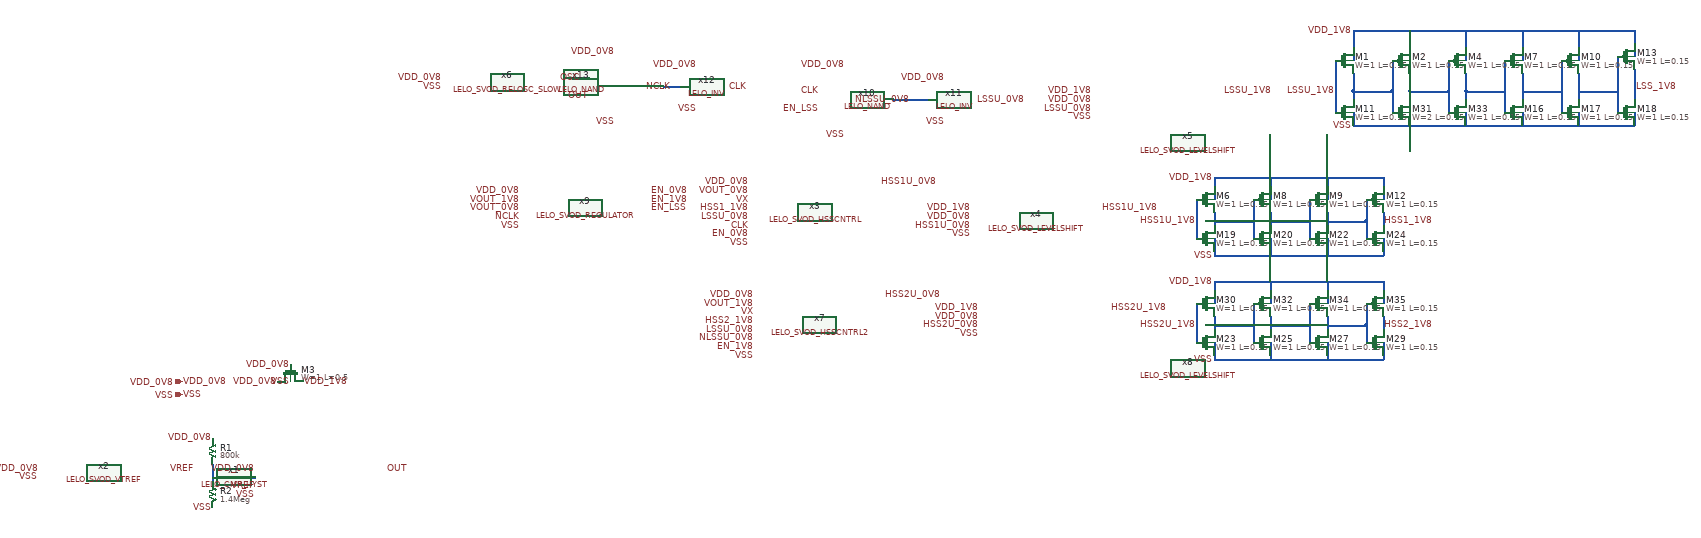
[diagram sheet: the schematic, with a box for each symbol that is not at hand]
v {xschem version=3.4.8RC file_version=1.2}
G {}
K {}
V {}
S {}
E {}
N -240 -50 -240 -10 {lab=#net1}
N -240 -20 -140 -20 {lab=#net1}
N 2390 -860 2390 -830 {lab=VSS}
N 2780 -950 2780 -890 {lab=#net2}
N 2780 -860 2780 -830 {lab=VSS}
N 2740 -980 2740 -860 {lab=#net3}
N 2390 -910 2480 -910 {lab=#net4}
N 2910 -950 2910 -890 {lab=#net5}
N 2910 -860 2910 -830 {lab=VSS}
N 2870 -980 2870 -860 {lab=#net2}
N 2780 -910 2870 -910 {lab=#net2}
N 3040 -960 3040 -890 {lab=LSS_1V8}
N 3040 -860 3040 -830 {lab=VSS}
N 3000 -990 3000 -860 {lab=#net5}
N 2910 -910 3000 -910 {lab=#net5}
N 2390 -1050 2970 -1050 {lab=VDD_1V8}
N 2780 -1050 2780 -1010 {lab=VDD_1V8}
N 2910 -1050 2910 -1010 {lab=VDD_1V8}
N 3040 -1050 3040 -1020 {lab=VDD_1V8}
N 2390 -1050 2390 -1010 {lab=VDD_1V8}
N 2390 -950 2390 -910 {lab=#net4}
N 2390 -910 2390 -890 {lab=#net4}
N 2350 -980 2350 -910 {lab=LSSU_1V8}
N 2350 -910 2350 -860 {lab=LSSU_1V8}
N 2070 -710 2070 -690 {lab=VDD_1V8}
N 2200 -710 2200 -690 {lab=VDD_1V8}
N 2070 -570 2070 -540 {lab=VSS}
N 2200 -570 2200 -540 {lab=VSS}
N 2030 -660 2030 -610 {lab=HSS1U_1V8}
N 2030 -610 2030 -570 {lab=HSS1U_1V8}
N 2070 -630 2070 -600 {lab=#net6}
N 2070 -540 2070 -530 {lab=VSS}
N 2070 -610 2160 -610 {lab=#net6}
N 2160 -660 2160 -610 {lab=#net6}
N 2160 -610 2160 -570 {lab=#net6}
N 2200 -630 2200 -600 {lab=#net7}
N 2200 -540 2200 -530 {lab=VSS}
N 2330 -710 2330 -690 {lab=VDD_1V8}
N 2330 -570 2330 -540 {lab=VSS}
N 2200 -610 2290 -610 {lab=#net7}
N 2290 -660 2290 -610 {lab=#net7}
N 2290 -610 2290 -570 {lab=#net7}
N 2330 -630 2330 -600 {lab=#net8}
N 2330 -540 2330 -530 {lab=VSS}
N 2460 -710 2460 -690 {lab=VDD_1V8}
N 2460 -570 2460 -540 {lab=VSS}
N 2420 -660 2420 -610 {lab=#net8}
N 2420 -610 2420 -570 {lab=#net8}
N 2460 -630 2460 -600 {lab=HSS1_1V8}
N 2460 -540 2460 -530 {lab=VSS}
N 2390 -1010 2390 -980 {lab=VDD_1V8}
N 2780 -1010 2780 -980 {lab=VDD_1V8}
N 2910 -1010 2910 -980 {lab=VDD_1V8}
N 3040 -1020 3040 -990 {lab=VDD_1V8}
N 2070 -690 2070 -660 {lab=VDD_1V8}
N 2200 -690 2200 -660 {lab=VDD_1V8}
N 2330 -690 2330 -660 {lab=VDD_1V8}
N 2520 -860 2520 -830 {lab=VSS}
N 2520 -910 2610 -910 {lab=#net9}
N 2520 -1050 2520 -1010 {lab=VDD_1V8}
N 2520 -950 2520 -910 {lab=#net9}
N 2520 -910 2520 -890 {lab=#net9}
N 2480 -980 2480 -910 {lab=#net4}
N 2480 -910 2480 -860 {lab=#net4}
N 2520 -1010 2520 -980 {lab=VDD_1V8}
N 2650 -860 2650 -830 {lab=VSS}
N 2650 -910 2740 -910 {lab=#net3}
N 2650 -1050 2650 -1010 {lab=VDD_1V8}
N 2650 -950 2650 -910 {lab=#net3}
N 2650 -910 2650 -890 {lab=#net3}
N 2610 -980 2610 -910 {lab=#net9}
N 2610 -910 2610 -860 {lab=#net9}
N 2650 -1010 2650 -980 {lab=VDD_1V8}
N 2330 -610 2420 -610 {lab=#net8}
N 2070 -710 2460 -710 {lab=VDD_1V8}
N 2460 -690 2460 -660 {lab=VDD_1V8}
N 2970 -1050 3040 -1050 {lab=VDD_1V8}
N 2390 -830 3040 -830 {lab=VSS}
N 2070 -530 2460 -530 {lab=VSS}
N 2070 -470 2070 -450 {lab=VDD_1V8}
N 2200 -470 2200 -450 {lab=VDD_1V8}
N 2070 -330 2070 -300 {lab=VSS}
N 2200 -330 2200 -300 {lab=VSS}
N 2030 -420 2030 -370 {lab=HSS2U_1V8}
N 2030 -370 2030 -330 {lab=HSS2U_1V8}
N 2070 -390 2070 -360 {lab=#net10}
N 2070 -300 2070 -290 {lab=VSS}
N 2070 -370 2160 -370 {lab=#net10}
N 2160 -420 2160 -370 {lab=#net10}
N 2160 -370 2160 -330 {lab=#net10}
N 2200 -390 2200 -360 {lab=#net11}
N 2200 -300 2200 -290 {lab=VSS}
N 2330 -470 2330 -450 {lab=VDD_1V8}
N 2330 -330 2330 -300 {lab=VSS}
N 2200 -370 2290 -370 {lab=#net11}
N 2290 -420 2290 -370 {lab=#net11}
N 2290 -370 2290 -330 {lab=#net11}
N 2330 -390 2330 -360 {lab=#net12}
N 2330 -300 2330 -290 {lab=VSS}
N 2460 -470 2460 -450 {lab=VDD_1V8}
N 2460 -330 2460 -300 {lab=VSS}
N 2420 -420 2420 -370 {lab=#net12}
N 2420 -370 2420 -330 {lab=#net12}
N 2460 -390 2460 -360 {lab=HSS2_1V8}
N 2460 -300 2460 -290 {lab=VSS}
N 2070 -450 2070 -420 {lab=VDD_1V8}
N 2200 -450 2200 -420 {lab=VDD_1V8}
N 2330 -450 2330 -420 {lab=VDD_1V8}
N 2330 -370 2420 -370 {lab=#net12}
N 2070 -470 2460 -470 {lab=VDD_1V8}
N 2460 -450 2460 -420 {lab=VDD_1V8}
N 2070 -290 2460 -290 {lab=VSS}
N 1330 -890 1410 -890 {lab=NLSSU_0V8}
N 590 -940 630 -940 {lab=OSC}
N 800 -920 840 -920 {lab=NCLK}
C {LELO_SVOD_SKY130A/LELO_CMP_HYST.sym} 10 -10 0 0 {name=x1}
C {devices/ipin.sym} -310 -240 0 0 {name=p1 lab=VDD_0V8}
C {devices/lab_pin.sym} -310 -240 0 1 {name=p2 sig_type=std_logic lab=VDD_0V8}
C {devices/ipin.sym} -310 -210 0 0 {name=p3 lab=VSS}
C {devices/lab_pin.sym} -310 -210 0 1 {name=p4 sig_type=std_logic lab=VSS}
C {devices/lab_pin.sym} -140 20 0 0 {name=p5 sig_type=std_logic lab=VSS}
C {devices/lab_pin.sym} 160 -40 0 1 {name=p7 sig_type=std_logic lab=OUT}
C {LELO_SVOD_SKY130A/LELO_SVOD_VTREF.sym} -490 -30 0 0 {name=x2}
C {devices/lab_pin.sym} -340 -40 0 1 {name=p8 sig_type=std_logic lab=VREF}
C {devices/lab_pin.sym} -140 0 0 0 {name=p9 sig_type=std_logic lab=VREF}
C {devices/lab_pin.sym} -640 -20 0 0 {name=p11 sig_type=std_logic lab=VSS}
C {devices/res.sym} -240 -80 0 0 {name=R1
value=800k
footprint=1206
device=resistor
m=1}
C {devices/res.sym} -240 20 0 0 {name=R2
value=1.4Meg
footprint=1206
device=resistor
m=1}
C {devices/lab_pin.sym} -240 50 0 0 {name=p12 sig_type=std_logic lab=VSS}
C {devices/lab_pin.sym} 3040 -920 0 1 {name=p30 sig_type=std_logic lab=LSS_1V8}
C {sky130_fd_pr/nfet_01v8.sym} 2370 -860 0 0 {name=M11
W=1
L=0.15
nf=1 
mult=1
ad="expr('int((@nf + 1)/2) * @W / @nf * 0.29')"
pd="expr('2*int((@nf + 1)/2) * (@W / @nf + 0.29)')"
as="expr('int((@nf + 2)/2) * @W / @nf * 0.29')"
ps="expr('2*int((@nf + 2)/2) * (@W / @nf + 0.29)')"
nrd="expr('0.29 / @W ')" nrs="expr('0.29 / @W ')"
sa=0 sb=0 sd=0
model=nfet_01v8
spiceprefix=X
}
C {sky130_fd_pr/nfet_01v8.sym} 2760 -860 0 0 {name=M16
W=1
L=0.15
nf=1 
mult=27
ad="expr('int((@nf + 1)/2) * @W / @nf * 0.29')"
pd="expr('2*int((@nf + 1)/2) * (@W / @nf + 0.29)')"
as="expr('int((@nf + 2)/2) * @W / @nf * 0.29')"
ps="expr('2*int((@nf + 2)/2) * (@W / @nf + 0.29)')"
nrd="expr('0.29 / @W ')" nrs="expr('0.29 / @W ')"
sa=0 sb=0 sd=0
model=nfet_01v8
spiceprefix=X
}
C {sky130_fd_pr/nfet_01v8.sym} 2890 -860 0 0 {name=M17
W=1
L=0.15
nf=1 
mult=81
ad="expr('int((@nf + 1)/2) * @W / @nf * 0.29')"
pd="expr('2*int((@nf + 1)/2) * (@W / @nf + 0.29)')"
as="expr('int((@nf + 2)/2) * @W / @nf * 0.29')"
ps="expr('2*int((@nf + 2)/2) * (@W / @nf + 0.29)')"
nrd="expr('0.29 / @W ')" nrs="expr('0.29 / @W ')"
sa=0 sb=0 sd=0
model=nfet_01v8
spiceprefix=X
}
C {sky130_fd_pr/nfet_01v8.sym} 3020 -860 0 0 {name=M18
W=1
L=0.15
nf=1 
mult=243
ad="expr('int((@nf + 1)/2) * @W / @nf * 0.29')"
pd="expr('2*int((@nf + 1)/2) * (@W / @nf + 0.29)')"
as="expr('int((@nf + 2)/2) * @W / @nf * 0.29')"
ps="expr('2*int((@nf + 2)/2) * (@W / @nf + 0.29)')"
nrd="expr('0.29 / @W ')" nrs="expr('0.29 / @W ')"
sa=0 sb=0 sd=0
model=nfet_01v8
spiceprefix=X
}
C {sky130_fd_pr/nfet_01v8.sym} 2050 -570 0 0 {name=M19
W=1
L=0.15
nf=1 
mult=1
ad="expr('int((@nf + 1)/2) * @W / @nf * 0.29')"
pd="expr('2*int((@nf + 1)/2) * (@W / @nf + 0.29)')"
as="expr('int((@nf + 2)/2) * @W / @nf * 0.29')"
ps="expr('2*int((@nf + 2)/2) * (@W / @nf + 0.29)')"
nrd="expr('0.29 / @W ')" nrs="expr('0.29 / @W ')"
sa=0 sb=0 sd=0
model=nfet_01v8
spiceprefix=X
}
C {sky130_fd_pr/nfet_01v8.sym} 2180 -570 0 0 {name=M20
W=1
L=0.15
nf=1 
mult=3
ad="expr('int((@nf + 1)/2) * @W / @nf * 0.29')"
pd="expr('2*int((@nf + 1)/2) * (@W / @nf + 0.29)')"
as="expr('int((@nf + 2)/2) * @W / @nf * 0.29')"
ps="expr('2*int((@nf + 2)/2) * (@W / @nf + 0.29)')"
nrd="expr('0.29 / @W ')" nrs="expr('0.29 / @W ')"
sa=0 sb=0 sd=0
model=nfet_01v8
spiceprefix=X
}
C {sky130_fd_pr/nfet_01v8.sym} 2310 -570 0 0 {name=M22
W=1
L=0.15
nf=1 
mult=9
ad="expr('int((@nf + 1)/2) * @W / @nf * 0.29')"
pd="expr('2*int((@nf + 1)/2) * (@W / @nf + 0.29)')"
as="expr('int((@nf + 2)/2) * @W / @nf * 0.29')"
ps="expr('2*int((@nf + 2)/2) * (@W / @nf + 0.29)')"
nrd="expr('0.29 / @W ')" nrs="expr('0.29 / @W ')"
sa=0 sb=0 sd=0
model=nfet_01v8
spiceprefix=X
}
C {sky130_fd_pr/nfet_01v8.sym} 2440 -570 0 0 {name=M24
W=1
L=0.15
nf=1 
mult=27
ad="expr('int((@nf + 1)/2) * @W / @nf * 0.29')"
pd="expr('2*int((@nf + 1)/2) * (@W / @nf + 0.29)')"
as="expr('int((@nf + 2)/2) * @W / @nf * 0.29')"
ps="expr('2*int((@nf + 2)/2) * (@W / @nf + 0.29)')"
nrd="expr('0.29 / @W ')" nrs="expr('0.29 / @W ')"
sa=0 sb=0 sd=0
model=nfet_01v8
spiceprefix=X
}
C {sky130_fd_pr/nfet_01v8.sym} 2500 -860 0 0 {name=M31
W=2
L=0.15
nf=1 
mult=3
ad="expr('int((@nf + 1)/2) * @W / @nf * 0.29')"
pd="expr('2*int((@nf + 1)/2) * (@W / @nf + 0.29)')"
as="expr('int((@nf + 2)/2) * @W / @nf * 0.29')"
ps="expr('2*int((@nf + 2)/2) * (@W / @nf + 0.29)')"
nrd="expr('0.29 / @W ')" nrs="expr('0.29 / @W ')"
sa=0 sb=0 sd=0
model=nfet_01v8
spiceprefix=X
}
C {sky130_fd_pr/nfet_01v8.sym} 2630 -860 0 0 {name=M33
W=1
L=0.15
nf=1 
mult=9
ad="expr('int((@nf + 1)/2) * @W / @nf * 0.29')"
pd="expr('2*int((@nf + 1)/2) * (@W / @nf + 0.29)')"
as="expr('int((@nf + 2)/2) * @W / @nf * 0.29')"
ps="expr('2*int((@nf + 2)/2) * (@W / @nf + 0.29)')"
nrd="expr('0.29 / @W ')" nrs="expr('0.29 / @W ')"
sa=0 sb=0 sd=0
model=nfet_01v8
spiceprefix=X
}
C {devices/lab_pin.sym} 1520 -890 0 1 {name=p14 sig_type=std_logic lab=LSSU_0V8}
C {LELO_SVOD_SKY130A/LELO_SVOD_HSSCNTRL.sym} 1150 -630 0 0 {name=x3}
C {devices/lab_pin.sym} 1300 -700 2 0 {name=p22 sig_type=std_logic lab=HSS1U_0V8}
C {devices/lab_pin.sym} 1000 -660 2 1 {name=p26 sig_type=std_logic lab=VX}
C {devices/lab_pin.sym} 1000 -680 0 0 {name=p27 sig_type=std_logic lab=VOUT_0V8}
C {LELO_SVOD_SKY130A/LELO_SVOD_LEVELSHIFT.sym} 1660 -610 0 0 {name=x4}
C {LELO_SVOD_SKY130A/LELO_SVOD_LEVELSHIFT.sym} 1940 -880 0 0 {name=x5}
C {devices/lab_pin.sym} 1810 -640 2 0 {name=p15 sig_type=std_logic lab=HSS1U_1V8}
C {devices/lab_pin.sym} 2090 -910 0 1 {name=p23 sig_type=std_logic lab=LSSU_1V8}
C {sky130_fd_pr/pfet_01v8_hvt.sym} 2050 -660 0 0 {name=M6
W=1
L=0.15
nf=1
mult=1
ad="expr('int((@nf + 1)/2) * @W / @nf * 0.29')"
pd="expr('2*int((@nf + 1)/2) * (@W / @nf + 0.29)')"
as="expr('int((@nf + 2)/2) * @W / @nf * 0.29')"
ps="expr('2*int((@nf + 2)/2) * (@W / @nf + 0.29)')"
nrd="expr('0.29 / @W ')" nrs="expr('0.29 / @W ')"
sa=0 sb=0 sd=0
model=pfet_01v8_hvt
spiceprefix=X
}
C {sky130_fd_pr/pfet_01v8_hvt.sym} 2180 -660 0 0 {name=M8
W=1
L=0.15
nf=1
mult=3
ad="expr('int((@nf + 1)/2) * @W / @nf * 0.29')"
pd="expr('2*int((@nf + 1)/2) * (@W / @nf + 0.29)')"
as="expr('int((@nf + 2)/2) * @W / @nf * 0.29')"
ps="expr('2*int((@nf + 2)/2) * (@W / @nf + 0.29)')"
nrd="expr('0.29 / @W ')" nrs="expr('0.29 / @W ')"
sa=0 sb=0 sd=0
model=pfet_01v8_hvt
spiceprefix=X
}
C {sky130_fd_pr/pfet_01v8_hvt.sym} 2310 -660 0 0 {name=M9
W=1
L=0.15
nf=1
mult=9
ad="expr('int((@nf + 1)/2) * @W / @nf * 0.29')"
pd="expr('2*int((@nf + 1)/2) * (@W / @nf + 0.29)')"
as="expr('int((@nf + 2)/2) * @W / @nf * 0.29')"
ps="expr('2*int((@nf + 2)/2) * (@W / @nf + 0.29)')"
nrd="expr('0.29 / @W ')" nrs="expr('0.29 / @W ')"
sa=0 sb=0 sd=0
model=pfet_01v8_hvt
spiceprefix=X
}
C {sky130_fd_pr/pfet_01v8_hvt.sym} 2440 -660 0 0 {name=M12
W=1
L=0.15
nf=1
mult=27
ad="expr('int((@nf + 1)/2) * @W / @nf * 0.29')"
pd="expr('2*int((@nf + 1)/2) * (@W / @nf + 0.29)')"
as="expr('int((@nf + 2)/2) * @W / @nf * 0.29')"
ps="expr('2*int((@nf + 2)/2) * (@W / @nf + 0.29)')"
nrd="expr('0.29 / @W ')" nrs="expr('0.29 / @W ')"
sa=0 sb=0 sd=0
model=pfet_01v8_hvt
spiceprefix=X
}
C {sky130_fd_pr/pfet_01v8_hvt.sym} 2370 -980 0 0 {name=M1
W=1
L=0.15
nf=1
mult=1
ad="expr('int((@nf + 1)/2) * @W / @nf * 0.29')"
pd="expr('2*int((@nf + 1)/2) * (@W / @nf + 0.29)')"
as="expr('int((@nf + 2)/2) * @W / @nf * 0.29')"
ps="expr('2*int((@nf + 2)/2) * (@W / @nf + 0.29)')"
nrd="expr('0.29 / @W ')" nrs="expr('0.29 / @W ')"
sa=0 sb=0 sd=0
model=pfet_01v8_hvt
spiceprefix=X
}
C {sky130_fd_pr/pfet_01v8_hvt.sym} 2500 -980 0 0 {name=M2
W=1
L=0.15
nf=1
mult=3
ad="expr('int((@nf + 1)/2) * @W / @nf * 0.29')"
pd="expr('2*int((@nf + 1)/2) * (@W / @nf + 0.29)')"
as="expr('int((@nf + 2)/2) * @W / @nf * 0.29')"
ps="expr('2*int((@nf + 2)/2) * (@W / @nf + 0.29)')"
nrd="expr('0.29 / @W ')" nrs="expr('0.29 / @W ')"
sa=0 sb=0 sd=0
model=pfet_01v8_hvt
spiceprefix=X
}
C {sky130_fd_pr/pfet_01v8_hvt.sym} 2630 -980 0 0 {name=M4
W=1
L=0.15
nf=1
mult=9
ad="expr('int((@nf + 1)/2) * @W / @nf * 0.29')"
pd="expr('2*int((@nf + 1)/2) * (@W / @nf + 0.29)')"
as="expr('int((@nf + 2)/2) * @W / @nf * 0.29')"
ps="expr('2*int((@nf + 2)/2) * (@W / @nf + 0.29)')"
nrd="expr('0.29 / @W ')" nrs="expr('0.29 / @W ')"
sa=0 sb=0 sd=0
model=pfet_01v8_hvt
spiceprefix=X
}
C {sky130_fd_pr/pfet_01v8_hvt.sym} 2760 -980 0 0 {name=M7
W=1
L=0.15
nf=1
mult=27
ad="expr('int((@nf + 1)/2) * @W / @nf * 0.29')"
pd="expr('2*int((@nf + 1)/2) * (@W / @nf + 0.29)')"
as="expr('int((@nf + 2)/2) * @W / @nf * 0.29')"
ps="expr('2*int((@nf + 2)/2) * (@W / @nf + 0.29)')"
nrd="expr('0.29 / @W ')" nrs="expr('0.29 / @W ')"
sa=0 sb=0 sd=0
model=pfet_01v8_hvt
spiceprefix=X
}
C {sky130_fd_pr/pfet_01v8_hvt.sym} 2890 -980 0 0 {name=M10
W=1
L=0.15
nf=1
mult=81
ad="expr('int((@nf + 1)/2) * @W / @nf * 0.29')"
pd="expr('2*int((@nf + 1)/2) * (@W / @nf + 0.29)')"
as="expr('int((@nf + 2)/2) * @W / @nf * 0.29')"
ps="expr('2*int((@nf + 2)/2) * (@W / @nf + 0.29)')"
nrd="expr('0.29 / @W ')" nrs="expr('0.29 / @W ')"
sa=0 sb=0 sd=0
model=pfet_01v8_hvt
spiceprefix=X
}
C {sky130_fd_pr/pfet_01v8_hvt.sym} 3020 -990 0 0 {name=M13
W=1
L=0.15
nf=1
mult=243
ad="expr('int((@nf + 1)/2) * @W / @nf * 0.29')"
pd="expr('2*int((@nf + 1)/2) * (@W / @nf + 0.29)')"
as="expr('int((@nf + 2)/2) * @W / @nf * 0.29')"
ps="expr('2*int((@nf + 2)/2) * (@W / @nf + 0.29)')"
nrd="expr('0.29 / @W ')" nrs="expr('0.29 / @W ')"
sa=0 sb=0 sd=0
model=pfet_01v8_hvt
spiceprefix=X
}
C {devices/lab_pin.sym} 1510 -600 2 1 {name=p16 sig_type=std_logic lab=HSS1U_0V8}
C {devices/lab_pin.sym} 2030 -610 2 1 {name=p17 sig_type=std_logic lab=HSS1U_1V8}
C {devices/lab_pin.sym} 290 -940 0 0 {name=p18 sig_type=std_logic lab=VDD_0V8}
C {devices/lab_pin.sym} 1000 -700 0 0 {name=p21 sig_type=std_logic lab=VDD_0V8}
C {devices/lab_pin.sym} 1510 -620 0 0 {name=p28 sig_type=std_logic lab=VDD_0V8}
C {devices/lab_pin.sym} 1790 -890 0 0 {name=p29 sig_type=std_logic lab=VDD_0V8}
C {devices/lab_pin.sym} 1510 -640 0 0 {name=p31 sig_type=std_logic lab=VDD_1V8}
C {devices/lab_pin.sym} 1790 -910 0 0 {name=p32 sig_type=std_logic lab=VDD_1V8}
C {devices/lab_pin.sym} 2070 -710 0 0 {name=p33 sig_type=std_logic lab=VDD_1V8}
C {devices/lab_pin.sym} 2390 -1050 0 0 {name=p34 sig_type=std_logic lab=VDD_1V8}
C {devices/lab_pin.sym} 1790 -870 0 0 {name=p37 sig_type=std_logic lab=LSSU_0V8}
C {devices/lab_pin.sym} 2350 -910 0 0 {name=p38 sig_type=std_logic lab=LSSU_1V8}
C {devices/lab_pin.sym} 2460 -610 2 0 {name=p39 sig_type=std_logic lab=HSS1_1V8}
C {devices/lab_pin.sym} 1000 -620 0 0 {name=p25 sig_type=std_logic lab=LSSU_0V8}
C {devices/lab_pin.sym} 1000 -640 0 0 {name=p49 sig_type=std_logic lab=HSS1_1V8}
C {devices/lab_pin.sym} 880 -970 1 0 {name=p51 sig_type=std_logic lab=VDD_0V8}
C {LELO_SVOD_SKY130A/LELO_SVOD_HSSCNTRL2.sym} 1160 -370 0 0 {name=x7}
C {devices/lab_pin.sym} 1010 -400 2 1 {name=p48 sig_type=std_logic lab=VX}
C {devices/lab_pin.sym} 1010 -440 0 0 {name=p50 sig_type=std_logic lab=VDD_0V8}
C {devices/lab_pin.sym} 1010 -420 0 0 {name=p53 sig_type=std_logic lab=VOUT_1V8}
C {devices/lab_pin.sym} 1010 -360 0 0 {name=p54 sig_type=std_logic lab=LSSU_0V8}
C {devices/lab_pin.sym} 1310 -440 2 0 {name=p57 sig_type=std_logic lab=HSS2U_0V8}
C {LELO_SVOD_SKY130A/LELO_SVOD_LEVELSHIFT.sym} 1680 -380 0 0 {name=x8}
C {devices/lab_pin.sym} 1830 -410 2 0 {name=p58 sig_type=std_logic lab=HSS2U_1V8}
C {devices/lab_pin.sym} 1530 -390 0 0 {name=p61 sig_type=std_logic lab=VDD_0V8}
C {devices/lab_pin.sym} 1530 -410 0 0 {name=p62 sig_type=std_logic lab=VDD_1V8}
C {devices/lab_pin.sym} 1530 -370 2 1 {name=p60 sig_type=std_logic lab=HSS2U_0V8}
C {sky130_fd_pr/nfet_01v8.sym} 2050 -330 0 0 {name=M23
W=1
L=0.15
nf=1 
mult=1
ad="expr('int((@nf + 1)/2) * @W / @nf * 0.29')"
pd="expr('2*int((@nf + 1)/2) * (@W / @nf + 0.29)')"
as="expr('int((@nf + 2)/2) * @W / @nf * 0.29')"
ps="expr('2*int((@nf + 2)/2) * (@W / @nf + 0.29)')"
nrd="expr('0.29 / @W ')" nrs="expr('0.29 / @W ')"
sa=0 sb=0 sd=0
model=nfet_01v8
spiceprefix=X
}
C {sky130_fd_pr/nfet_01v8.sym} 2180 -330 0 0 {name=M25
W=1
L=0.15
nf=1 
mult=3
ad="expr('int((@nf + 1)/2) * @W / @nf * 0.29')"
pd="expr('2*int((@nf + 1)/2) * (@W / @nf + 0.29)')"
as="expr('int((@nf + 2)/2) * @W / @nf * 0.29')"
ps="expr('2*int((@nf + 2)/2) * (@W / @nf + 0.29)')"
nrd="expr('0.29 / @W ')" nrs="expr('0.29 / @W ')"
sa=0 sb=0 sd=0
model=nfet_01v8
spiceprefix=X
}
C {sky130_fd_pr/nfet_01v8.sym} 2310 -330 0 0 {name=M27
W=1
L=0.15
nf=1 
mult=9
ad="expr('int((@nf + 1)/2) * @W / @nf * 0.29')"
pd="expr('2*int((@nf + 1)/2) * (@W / @nf + 0.29)')"
as="expr('int((@nf + 2)/2) * @W / @nf * 0.29')"
ps="expr('2*int((@nf + 2)/2) * (@W / @nf + 0.29)')"
nrd="expr('0.29 / @W ')" nrs="expr('0.29 / @W ')"
sa=0 sb=0 sd=0
model=nfet_01v8
spiceprefix=X
}
C {sky130_fd_pr/nfet_01v8.sym} 2440 -330 0 0 {name=M29
W=1
L=0.15
nf=1 
mult=27
ad="expr('int((@nf + 1)/2) * @W / @nf * 0.29')"
pd="expr('2*int((@nf + 1)/2) * (@W / @nf + 0.29)')"
as="expr('int((@nf + 2)/2) * @W / @nf * 0.29')"
ps="expr('2*int((@nf + 2)/2) * (@W / @nf + 0.29)')"
nrd="expr('0.29 / @W ')" nrs="expr('0.29 / @W ')"
sa=0 sb=0 sd=0
model=nfet_01v8
spiceprefix=X
}
C {sky130_fd_pr/pfet_01v8_hvt.sym} 2050 -420 0 0 {name=M30
W=1
L=0.15
nf=1
mult=1
ad="expr('int((@nf + 1)/2) * @W / @nf * 0.29')"
pd="expr('2*int((@nf + 1)/2) * (@W / @nf + 0.29)')"
as="expr('int((@nf + 2)/2) * @W / @nf * 0.29')"
ps="expr('2*int((@nf + 2)/2) * (@W / @nf + 0.29)')"
nrd="expr('0.29 / @W ')" nrs="expr('0.29 / @W ')"
sa=0 sb=0 sd=0
model=pfet_01v8_hvt
spiceprefix=X
}
C {sky130_fd_pr/pfet_01v8_hvt.sym} 2180 -420 0 0 {name=M32
W=1
L=0.15
nf=1
mult=3
ad="expr('int((@nf + 1)/2) * @W / @nf * 0.29')"
pd="expr('2*int((@nf + 1)/2) * (@W / @nf + 0.29)')"
as="expr('int((@nf + 2)/2) * @W / @nf * 0.29')"
ps="expr('2*int((@nf + 2)/2) * (@W / @nf + 0.29)')"
nrd="expr('0.29 / @W ')" nrs="expr('0.29 / @W ')"
sa=0 sb=0 sd=0
model=pfet_01v8_hvt
spiceprefix=X
}
C {sky130_fd_pr/pfet_01v8_hvt.sym} 2310 -420 0 0 {name=M34
W=1
L=0.15
nf=1
mult=9
ad="expr('int((@nf + 1)/2) * @W / @nf * 0.29')"
pd="expr('2*int((@nf + 1)/2) * (@W / @nf + 0.29)')"
as="expr('int((@nf + 2)/2) * @W / @nf * 0.29')"
ps="expr('2*int((@nf + 2)/2) * (@W / @nf + 0.29)')"
nrd="expr('0.29 / @W ')" nrs="expr('0.29 / @W ')"
sa=0 sb=0 sd=0
model=pfet_01v8_hvt
spiceprefix=X
}
C {sky130_fd_pr/pfet_01v8_hvt.sym} 2440 -420 0 0 {name=M35
W=1
L=0.15
nf=1
mult=27
ad="expr('int((@nf + 1)/2) * @W / @nf * 0.29')"
pd="expr('2*int((@nf + 1)/2) * (@W / @nf + 0.29)')"
as="expr('int((@nf + 2)/2) * @W / @nf * 0.29')"
ps="expr('2*int((@nf + 2)/2) * (@W / @nf + 0.29)')"
nrd="expr('0.29 / @W ')" nrs="expr('0.29 / @W ')"
sa=0 sb=0 sd=0
model=pfet_01v8_hvt
spiceprefix=X
}
C {devices/lab_pin.sym} 2070 -470 0 0 {name=p65 sig_type=std_logic lab=VDD_1V8}
C {devices/lab_pin.sym} 2460 -370 2 0 {name=p66 sig_type=std_logic lab=HSS2_1V8}
C {devices/lab_pin.sym} 2030 -370 2 1 {name=p64 sig_type=std_logic lab=HSS2U_1V8}
C {devices/lab_pin.sym} 1010 -380 2 1 {name=p67 sig_type=std_logic lab=HSS2_1V8}
C {LELO_SVOD_SKY130A/LELO_SVOD_REGULATOR.sym} 620 -640 0 0 {name=x9}
C {devices/lab_pin.sym} 770 -680 0 1 {name=p19 sig_type=std_logic lab=EN_0V8}
C {devices/lab_pin.sym} 1000 -580 0 0 {name=p55 sig_type=std_logic lab=EN_0V8}
C {devices/lab_pin.sym} 770 -660 0 1 {name=p69 sig_type=std_logic lab=EN_1V8}
C {devices/lab_pin.sym} 1010 -320 0 0 {name=p70 sig_type=std_logic lab=EN_1V8}
C {devices/lab_pin.sym} 470 -640 0 0 {name=p71 sig_type=std_logic lab=VOUT_0V8}
C {devices/lab_pin.sym} 470 -660 0 0 {name=p72 sig_type=std_logic lab=VOUT_1V8}
C {devices/lab_pin.sym} 470 -680 0 0 {name=p46 sig_type=std_logic lab=VDD_0V8}
C {devices/lab_pin.sym} 820 -920 3 1 {name=p76 sig_type=std_logic lab=NCLK}
C {LELO_SVOD_SKY130A/LELO_NAND.sym} 1240 -890 0 0 {name=x10}
C {LELO_SVOD_SKY130A/LELO_INV.sym} 1470 -890 0 0 {name=x11}
C {devices/lab_pin.sym} 1220 -970 0 0 {name=p81 sig_type=std_logic lab=VDD_0V8}
C {devices/lab_pin.sym} 1450 -940 0 0 {name=p82 sig_type=std_logic lab=VDD_0V8}
C {devices/lab_pin.sym} 770 -640 0 1 {name=p85 sig_type=std_logic lab=EN_LSS}
C {devices/lab_pin.sym} 1160 -870 0 0 {name=p83 sig_type=std_logic lab=EN_LSS}
C {devices/lab_pin.sym} 470 -620 0 0 {name=p74 sig_type=std_logic lab=NCLK}
C {devices/lab_pin.sym} 950 -920 0 1 {name=p84 sig_type=std_logic lab=CLK}
C {devices/lab_pin.sym} 1160 -910 0 0 {name=p78 sig_type=std_logic lab=CLK}
C {devices/lab_pin.sym} 1370 -890 1 1 {name=p86 sig_type=std_logic lab=NLSSU_0V8}
C {devices/lab_pin.sym} 1010 -340 2 1 {name=p88 sig_type=std_logic lab=NLSSU_0V8}
C {devices/lab_pin.sym} 1000 -600 0 0 {name=p87 sig_type=std_logic lab=CLK}
C {devices/lab_pin.sym} 1220 -810 3 0 {name=p20 sig_type=std_logic lab=VSS}
C {devices/lab_pin.sym} 880 -870 3 0 {name=p24 sig_type=std_logic lab=VSS}
C {LELO_SVOD_SKY130A/LELO_INV.sym} 900 -920 0 0 {name=x12}
C {devices/lab_pin.sym} 470 -600 0 0 {name=p35 sig_type=std_logic lab=VSS}
C {devices/lab_pin.sym} 1000 -560 0 0 {name=p36 sig_type=std_logic lab=VSS}
C {devices/lab_pin.sym} 1010 -300 0 0 {name=p40 sig_type=std_logic lab=VSS}
C {devices/lab_pin.sym} 1530 -350 0 0 {name=p41 sig_type=std_logic lab=VSS}
C {devices/lab_pin.sym} 1510 -580 0 0 {name=p42 sig_type=std_logic lab=VSS}
C {devices/lab_pin.sym} 1790 -850 0 0 {name=p43 sig_type=std_logic lab=VSS}
C {devices/lab_pin.sym} 2070 -530 0 0 {name=p44 sig_type=std_logic lab=VSS}
C {devices/lab_pin.sym} 2070 -290 0 0 {name=p45 sig_type=std_logic lab=VSS}
C {devices/lab_pin.sym} 2390 -830 0 0 {name=p47 sig_type=std_logic lab=VSS}
C {devices/lab_pin.sym} 290 -920 0 0 {name=p52 sig_type=std_logic lab=VSS}
C {devices/lab_pin.sym} 1450 -840 3 0 {name=p56 sig_type=std_logic lab=VSS}
C {LELO_SVOD_SKY130A/LELO_NAND.sym} 710 -920 0 0 {name=x13}
C {devices/lab_pin.sym} 690 -1000 0 0 {name=p59 sig_type=std_logic lab=VDD_0V8}
C {devices/lab_pin.sym} 690 -840 3 0 {name=p63 sig_type=std_logic lab=VSS}
C {devices/lab_pin.sym} 610 -940 3 1 {name=p68 sig_type=std_logic lab=OSC}
C {devices/lab_pin.sym} 630 -900 0 0 {name=p73 sig_type=std_logic lab=OUT}
C {devices/lab_pin.sym} -140 -40 0 0 {name=p6 sig_type=std_logic lab=VDD_0V8}
C {devices/lab_pin.sym} -640 -40 0 0 {name=p10 sig_type=std_logic lab=VDD_0V8}
C {devices/lab_pin.sym} -240 -110 0 0 {name=p13 sig_type=std_logic lab=VDD_0V8}
C {sky130_fd_pr/nfet_03v3_nvt.sym} -60 -260 1 0 {name=M3
W=1
L=0.5
nf=1
mult=1
ad="expr('int((@nf + 1)/2) * @W / @nf * 0.29')"
pd="expr('2*int((@nf + 1)/2) * (@W / @nf + 0.29)')"
as="expr('int((@nf + 2)/2) * @W / @nf * 0.29')"
ps="expr('2*int((@nf + 2)/2) * (@W / @nf + 0.29)')"
nrd="expr('0.29 / @W ')" nrs="expr('0.29 / @W ')"
sa=0 sb=0 sd=0
model=nfet_03v3_nvt
spiceprefix=X
}
C {devices/lab_pin.sym} -90 -240 0 0 {name=p75 sig_type=std_logic lab=VDD_0V8}
C {devices/lab_pin.sym} -30 -240 0 1 {name=p77 sig_type=std_logic lab=VDD_1V8}
C {devices/lab_pin.sym} -60 -240 1 1 {name=p79 sig_type=std_logic lab=VSS}
C {devices/lab_pin.sym} -60 -280 1 0 {name=p80 sig_type=std_logic lab=VDD_0V8}
C {LELO_SVOD_SKY130A/LELO_SVOD_RELOSC_SLOW.sym} 440 -930 0 0 {name=x6}
